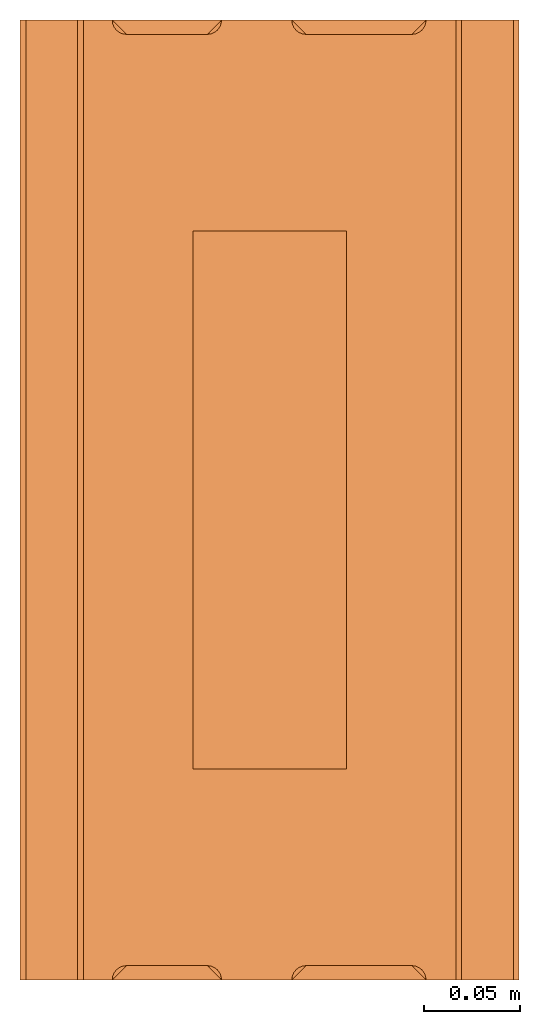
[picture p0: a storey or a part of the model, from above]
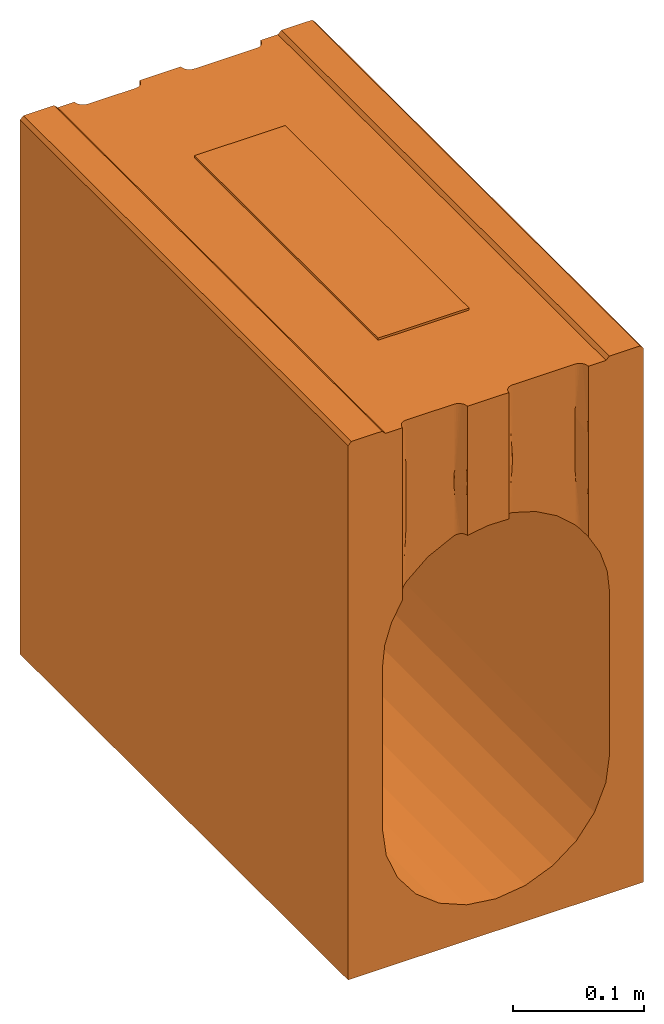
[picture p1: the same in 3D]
Properties of the parts of a building model (IFC2X3)

# File
Description: ViewDefinition [CoordinationView]
File name: 33303 - PD 200 F 30.3 Rodding Access 500mm LG.ifc
Time: 2013-10-11T12:58:24
Written by: Autodesk Revit 2013
Made in: 20120221_2030(x64)

# IfcProject, Project Number
LongName: Project Name; Phase: Project Status

# IfcSite, Default
RefLatitude: 42, 21, 30, 344238; RefLongitude: -71, -3, -35, -194702; RefElevation: 0 mm

# IfcBuilding
Pset_BuildingCommon - NumberOfStoreys: 2
Other - Client Name: Owner; Project Status: Project Status; Project Address: Enter address here; Project Number: Project Number; Project Issue Date: Issue Date; Project Name: Project Name

# IfcBuildingStorey (2)
Constraints - Elevation Base: 0
Graphics - Color: 0; Line Weight: 1; Symbol at End 2 Default: yes; Symbol: M_Level Head - Circle: M_Level Head - Circle; Line Pattern: Center; Symbol at End 1 Default: no
Identity Data - Structural: no; Building Story: yes
Dimensions - Computation Height: 0 mm
Name | LongName = Name | Elevation (mm) = Constraints, Elevation (mm)
B.O. Footing | B.O. Footing | -4600
T.O. Footing | T.O. Footing | -4300

# IfcBuildingElementProxy: 33303 - PD 200 F 30.3 Rodding Access 500mm LG, Civil-Drainage-Channel-ACO-RoadDrain 200:33303 - PD 200 F 30.3 Rodding Access 500mm LG:33303 - PD 200 F 30.3 Rodding Access 500mm LG:309971
In: B.O. Footing
Material: Acetal Resin, Black
Data - Product Dimensions: 500mm x 260mm x 500mm (LxWxH); Connection Pipe O.D: N/A; Concrete Surround Volume - Load Class F 900 - Concrete Pavement: 0.33m³/m; Installation - Concrete Grade: Refer to brochure; Product Weight: 66.0 Kg; Hydraulic Performance: http://www.aco.co.uk/download.php?id=256; ACO Hydraulic Design Software: http://www.acodesign.co.uk; Load Class: A 15 - F 900; Channel C.S.A: 0.061m²; Invert Depth: 470mm; Product Standard: BS EN 1433:2002, CE marked, Kitemarked
Construction - Closing End Cap: no; Access unit: yes; Inlet Outlet end cap: no; Channel 260mm Wide: no
Dimensions - Length: 500 mm; Volume: 33640670 mm3; Custom Void Length: 0 mm; Straight Void Length: 500 mm; Void Depth: -500 mm; I/O End Cap Void: 3500 mm; Pipe Depth: 5650 mm; Straight Void Start: 0 mm; Invert Depth.: 370 mm; Total Depth: 500 mm
Phasing - Phase Created: Phase 1
Constraints - Moves With Nearby Elements: no; Level: Level: T.O. Footing
Pset_BuildingElementProxyCommon - Reference: 33303 - PD 200 F 30.3 Rodding Access 500mm LG
Identity Data - Product Code: 33303; Model Description: Monolithic Channel drainage system; Telephone: +44 (0)1462 816666; Watermark 1: This file is the property of ACO Technologies PLC; Price: POA - contact ACO; Assembly Code: D2040; Assembly Description: Rain Water Drainage; OmniClass Number: 23.70.50.24; Maintenance guidelines: http://www.aco.co.uk/download.php?id=256; Type Comments: ACO RoadDrain 200 PD200F 30.3 Constant Depth Access Channel 500mm Long; OmniClass Title: Rainwater Removal; URL: www.aco.co.uk; Watermarked With: BIM Manager Premium Suite; Product Page URL: http://www.aco.co.uk/product_detail.php?id=21; Installation guidelines: http://www.aco.co.uk/download.php?id=256; Product brochure: http://www.aco.co.uk/download.php?id=256; Watermarked By: www.aco.co.uk; Manufacturer: ACO Technologies plc - ACO Water Management Division; e-mail Sales: customersupport@aco.co.uk; Watermark 2: This file is water marked and users are prohibited to reproduce, adapt, distribute this information; Cost: 0; Model: ACO RoadDrain 200 PD200F; Address: ACO Business Park, Hitchin Road, Shefford, Bedfordshire, United Kingdom SG17 5TE; e-mail Technical: technical@aco.co.uk; Fax: +44 (0)1462 815895
General - SerialNumber: 0.000000; TagNumber: 0.000000
Materials and Finishes - Channel Material: Vienite® Synthetic Resin Concrete; Grating Material: N/A; Access Cover/Frame Finish: Water Based Paint Coating; Grating Colour: N/A; End Cap Colour: N/A; End Cap Material: N/A; Access Cover/Frame Colour: Black; Channel Colour: Black; Grating Finish: N/A; Access Cover/Frame Material: Ductile Iron; Connection Pipe Colour: N/A; Connection Pipe Material: N/A
Green Building Properties - Access Cover/Frame Recyclable: Fully recyclable; Access Cover/Frame Recycled Material Content: Between 40% - 90%; End Cap Recycled Material Content: N/A; Channel Recycled Material Content: 20% minimum; End Cap Recyclable: N/A; Channel Recyclable: Fully recyclable
Other - Revision: 1; CreatedBy: www.aco.co.uk

# IfcOpeningElement: Recess (2)
In: T.O. Footing
Constraints - Related to Mass: no; Height Offset From Level: 0 mm; Level: Level: T.O. Footing; Room Bounding: yes
Dimensions - Thickness: 1550 mm; Volume: 40250500000 mm3; Area: 26010000 mm2; Perimeter: 20400 mm
Phasing - Phase Created: Phase 1
Structural - Enable Analytical Model: no; Structural: no
Analytical Properties - Thermal mass: 2039700; Absorptance: 0.1; Thermal Resistance (R): 1.79211; Heat Transfer Coefficient (U): 0.558; Roughness: 1
Construction - Function: 0; Default Thickness: 1550 mm
Graphics - Coarse Scale Fill Color: 0
Materials and Finishes - Structural Material: Grass

# IfcSlab: Floor:Generic Floor - 400mm, Floor:Generic Floor - 400mm:136436
In: T.O. Footing
PredefinedType: FLOOR; Material: Grass 50 mm, Earth 1500 mm
Constraints - Related to Mass: no; Height Offset From Level: 0 mm; Level: Level: T.O. Footing; Room Bounding: yes
Dimensions - Thickness: 1550 mm; Volume: 40250500000 mm3; Area: 26010000 mm2; Perimeter: 20400 mm
Phasing - Phase Created: Phase 1
Structural - Enable Analytical Model: no; Structural: no
Pset_SlabCommon - Reference: Generic Floor - 400mm; IsExternal: no; LoadBearing: yes
Analytical Properties - Thermal mass: 2039700; Absorptance: 0.1; Thermal Resistance (R): 1.79211; Heat Transfer Coefficient (U): 0.558; Roughness: 1
Construction - Function: 0; Default Thickness: 1550 mm
Graphics - Coarse Scale Fill Color: 0
Materials and Finishes - Structural Material: Grass
